VERSION 5.8 ;
BUSBITCHARS "[]" ;
DIVIDERCHAR "/" ;
UNITS
  DATABASE MICRONS 1000 ;
END UNITS
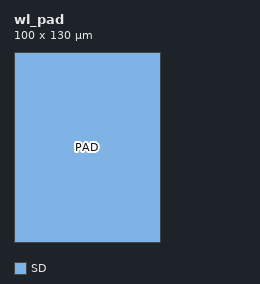
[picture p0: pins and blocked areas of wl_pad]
MACRO wl_pad
  CLASS PAD ;
  ORIGIN 0 0 ;
  FOREIGN wl_pad 0 0 ;
  SIZE 100 BY 130 ;
  SYMMETRY X Y ;
  PIN PAD
    DIRECTION INOUT ;
    USE SIGNAL ;
    PORT
      LAYER SD ;
        RECT 0 0 100 130 ;
    END
  END PAD
  OBS
    LAYER SD ;
      RECT 0 0 100 130 ;
  END
END wl_pad
END LIBRARY
